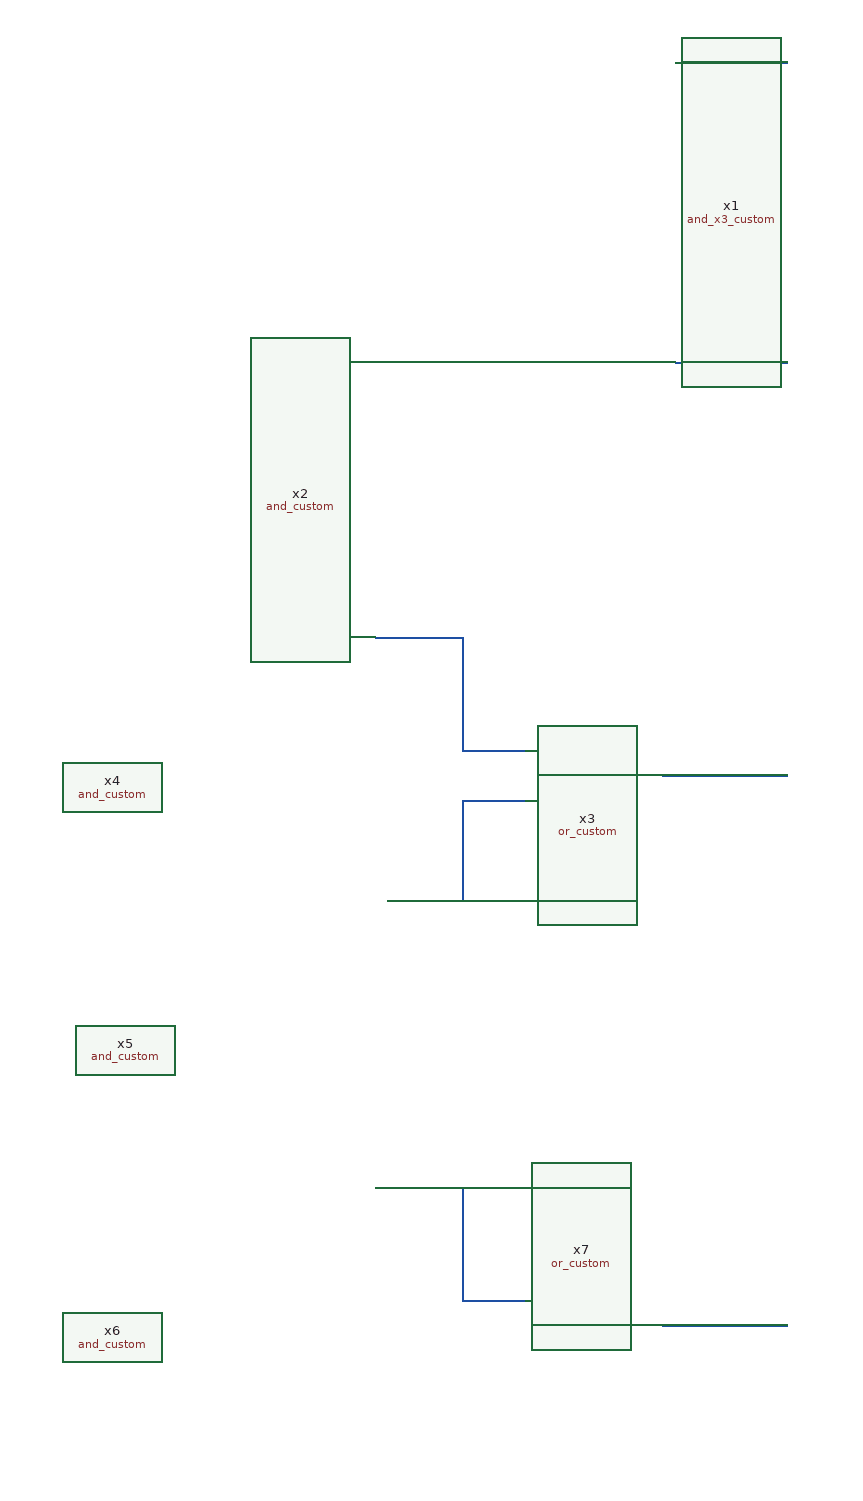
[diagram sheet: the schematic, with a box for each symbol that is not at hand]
v {xschem version=3.4.8RC file_version=1.2}
G {}
K {}
V {}
S {}
F {}
E {}
N 740 -1230 810 -1230 {lab=#net1}
N 810 -1230 810 -1140 {lab=#net1}
N 810 -1140 860 -1140 {lab=#net1}
N 810 -1100 860 -1100 {lab=#net2}
N 810 -1100 810 -1020 {lab=#net2}
N 750 -1020 810 -1020 {lab=#net2}
N 980 -1450 1070 -1450 {lab=#net3}
N 970 -1120 1070 -1120 {lab=#net4}
N 980 -1690 1070 -1690 {lab=#net5}
N 740 -790 810 -790 {lab=#net6}
N 810 -790 810 -700 {lab=#net6}
N 810 -700 860 -700 {lab=#net6}
N 970 -680 1070 -680 {lab=#net7}
C {/foss/designs/PhaseInterpolator/Custom_std_cells/and_x3_custom.sym} 790 -1600 0 0 {name=x1}
C {/foss/designs/PhaseInterpolator/Custom_std_cells/and_custom.sym} 770 -1330 0 0 {name=x2}
C {/foss/designs/PhaseInterpolator/Custom_std_cells/or_custom.sym} 840 -1050 0 0 {name=x3}
C {/foss/designs/PhaseInterpolator/Custom_std_cells/and_custom.sym} 530 -1110 0 0 {name=x4}
C {/foss/designs/PhaseInterpolator/Custom_std_cells/and_custom.sym} 540 -900 0 0 {name=x5}
C {/foss/designs/PhaseInterpolator/Custom_std_cells/and_custom.sym} 530 -670 0 0 {name=x6}
C {/foss/designs/PhaseInterpolator/Custom_std_cells/or_custom.sym} 840 -610 0 0 {name=x7}
